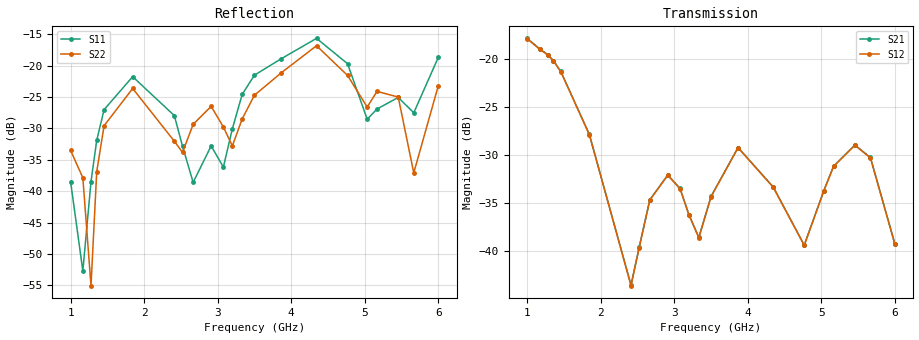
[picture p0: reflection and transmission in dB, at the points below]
!Agilent Technologies,E8364B,MY43040528,A.07.50.67
!Agilent E8364B: A.07.50.67
!Date: Sunday, March 01, 2026 17:03:57
!Correction: S11(Full 2 Port(1,2))
!S21(Full 2 Port(1,2))
!S12(Full 2 Port(1,2))
!S22(Full 2 Port(1,2))
!S2P File: Measurements: S11, S21, S12, S22:
# Hz S  dB  R 50
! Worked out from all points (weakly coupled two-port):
!   451 points, 1 GHz to 6 GHz, reference 50 ohm
!   highest |S21| = -17.83 dB at 1 GHz (marker M1); lowest = -43.6 dB at 2.411 GHz (marker M2)
!   lowest |S11| = -52.7 dB at 1.167 GHz (marker M3), VSWR 1.00, Z = 49.9 + j0.215 ohm
!   |S11| at or under -10 dB: start of sweep to end of sweep
!   |S22| runs from -55.0 to -16.8 dB; largest |S21 - S12| = 0.00063
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1e9  -38.46 24.3  -17.83 28.2  -17.88 28.3  -33.50 -3.3
1.166667e9  -52.69 111.8  -18.91 -21.5  -18.95 -21.5  -37.85 -4.2
1.277778e9  -38.47 -170.9  -19.52 -57.3  -19.56 -57.2  -55.04 55.8
1.355556e9  -31.89 -177.7  -20.14 -83.4  -20.18 -83.3  -36.88 116.6
1.455556e9  -27.01 160.7  -21.27 -117.2  -21.31 -117.1  -29.57 91.6
1.844444e9  -21.76 82.1  -27.85 118.8  -27.88 118.9  -23.64 -4.4
2.411111e9  -27.96 -4.9  -43.58 -129.0  -43.64 -128.9  -32.04 -84.1
2.522222e9  -32.83 -14.4  -39.62 140.3  -39.67 140.3  -33.82 -63.3
2.666667e9  -38.60 39.6  -34.67 67.0  -34.71 67.1  -29.35 -57.7
2.911111e9  -32.79 41.0  -32.08 -33.7  -32.12 -33.6  -26.49 -106.6
3.077778e9  -36.15 66.5  -33.49 -94.5  -33.54 -94.4  -29.77 -134.4
3.2e9  -30.06 92.6  -36.25 -128.3  -36.29 -128.3  -32.79 -119.0
3.333333e9  -24.59 78.7  -38.60 -137.8  -38.65 -137.8  -28.49 -105.5
3.5e9  -21.52 52.5  -34.31 -157.8  -34.35 -157.7  -24.71 -127.7
3.866667e9  -18.89 15.4  -29.22 73.5  -29.25 73.6  -21.13 -164.1
4.344444e9  -15.66 -51.2  -33.32 -103.1  -33.37 -103.1  -16.83 111.3
4.766667e9  -19.70 -115.3  -39.40 56.6  -39.44 56.7  -21.57 36.3
5.033333e9  -28.54 -114.8  -33.71 -98.2  -33.75 -98.2  -26.60 43.1
5.166667e9  -26.91 -85.3  -31.14 -160.6  -31.19 -160.5  -24.10 38.8
5.455556e9  -25.07 -107.6  -28.95 73.3  -28.99 73.3  -25.01 -19.8
5.666667e9  -27.51 -79.6  -30.26 -16.1  -30.31 -16.1  -37.08 -6.8
6e9  -18.69 -91.9  -39.30 -137.7  -39.34 -137.7  -23.21 -0.5
